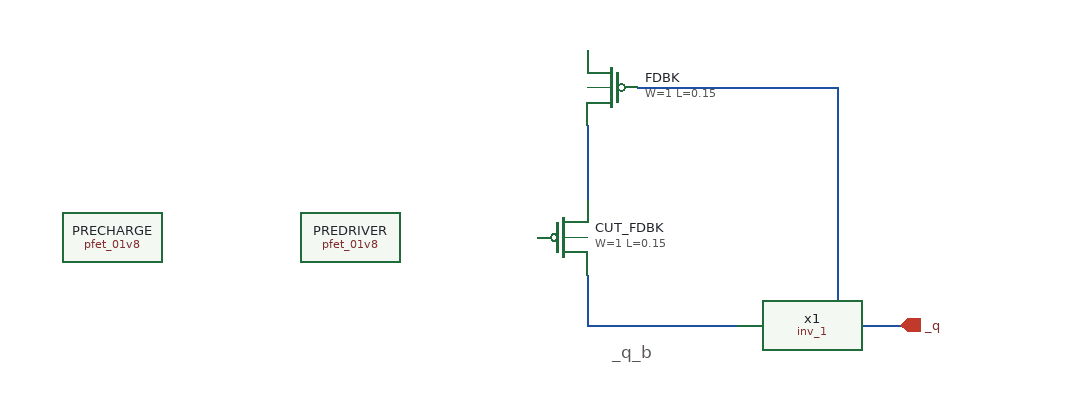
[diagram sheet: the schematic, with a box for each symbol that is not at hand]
v {xschem version=3.1.0 file_version=1.2
}
G {}
K {}
V {}
S {}
E {}
T {_q_b} 480 -120 0 0 0.4 0.4 {}
N 460 -290 460 -230 {
lab=#net1}
N 460 -170 460 -130 {
lab=#net2}
N 460 -130 580 -130 {
lab=#net2}
N 500 -320 650 -320 {
lab=_q}
N 660 -320 660 -130 {
lab=_q}
N 650 -320 660 -320 {
lab=_q}
N 660 -130 710 -130 {
lab=_q}
C {sky130_fd_pr/pfet_01v8.sym} 80 -200 0 0 {name=PRECHARGE
L=0.15
W=1
nf=1
mult=1
ad="'int((nf+1)/2) * W/nf * 0.29'" 
pd="'2*int((nf+1)/2) * (W/nf + 0.29)'"
as="'int((nf+2)/2) * W/nf * 0.29'" 
ps="'2*int((nf+2)/2) * (W/nf + 0.29)'"
nrd="'0.29 / W'" nrs="'0.29 / W'"
sa=0 sb=0 sd=0
model=pfet_01v8
spiceprefix=X
}
C {sky130_fd_pr/pfet_01v8.sym} 270 -200 0 0 {name=PREDRIVER
L=0.15
W=1
nf=1
mult=1
ad="'int((nf+1)/2) * W/nf * 0.29'" 
pd="'2*int((nf+1)/2) * (W/nf + 0.29)'"
as="'int((nf+2)/2) * W/nf * 0.29'" 
ps="'2*int((nf+2)/2) * (W/nf + 0.29)'"
nrd="'0.29 / W'" nrs="'0.29 / W'"
sa=0 sb=0 sd=0
model=pfet_01v8
spiceprefix=X
}
C {sky130_fd_pr/pfet_01v8.sym} 440 -200 0 0 {name=CUT_FDBK
L=0.15
W=1
nf=1
mult=1
ad="'int((nf+1)/2) * W/nf * 0.29'" 
pd="'2*int((nf+1)/2) * (W/nf + 0.29)'"
as="'int((nf+2)/2) * W/nf * 0.29'" 
ps="'2*int((nf+2)/2) * (W/nf + 0.29)'"
nrd="'0.29 / W'" nrs="'0.29 / W'"
sa=0 sb=0 sd=0
model=pfet_01v8
spiceprefix=X
}
C {sky130_fd_pr/pfet_01v8.sym} 480 -320 0 1 {name=FDBK
L=0.15
W=1
nf=1
mult=1
ad="'int((nf+1)/2) * W/nf * 0.29'" 
pd="'2*int((nf+1)/2) * (W/nf + 0.29)'"
as="'int((nf+2)/2) * W/nf * 0.29'" 
ps="'2*int((nf+2)/2) * (W/nf + 0.29)'"
nrd="'0.29 / W'" nrs="'0.29 / W'"
sa=0 sb=0 sd=0
model=pfet_01v8
spiceprefix=X
}
C {sky130_stdcells/inv_1.sym} 620 -130 0 0 {name=x1 VGND=VGND VNB=VNB VPB=VPB VPWR=VPWR prefix=sky130_fd_sc_hd__ }
C {devices/opin.sym} 710 -130 0 0 {name=p1 lab=_q}
